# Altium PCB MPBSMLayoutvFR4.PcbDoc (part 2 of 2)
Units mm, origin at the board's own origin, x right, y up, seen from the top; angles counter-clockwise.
Board outline 131.7 x 110.39 mm, 4 copper layers (Top Layer, Power, GroundPlane, Bottom Layer), stack 2.286 mm thick; 157 components, 77 nets, 430 pads, 122 vias.
Unrouted connection lines stored in the file: 1.

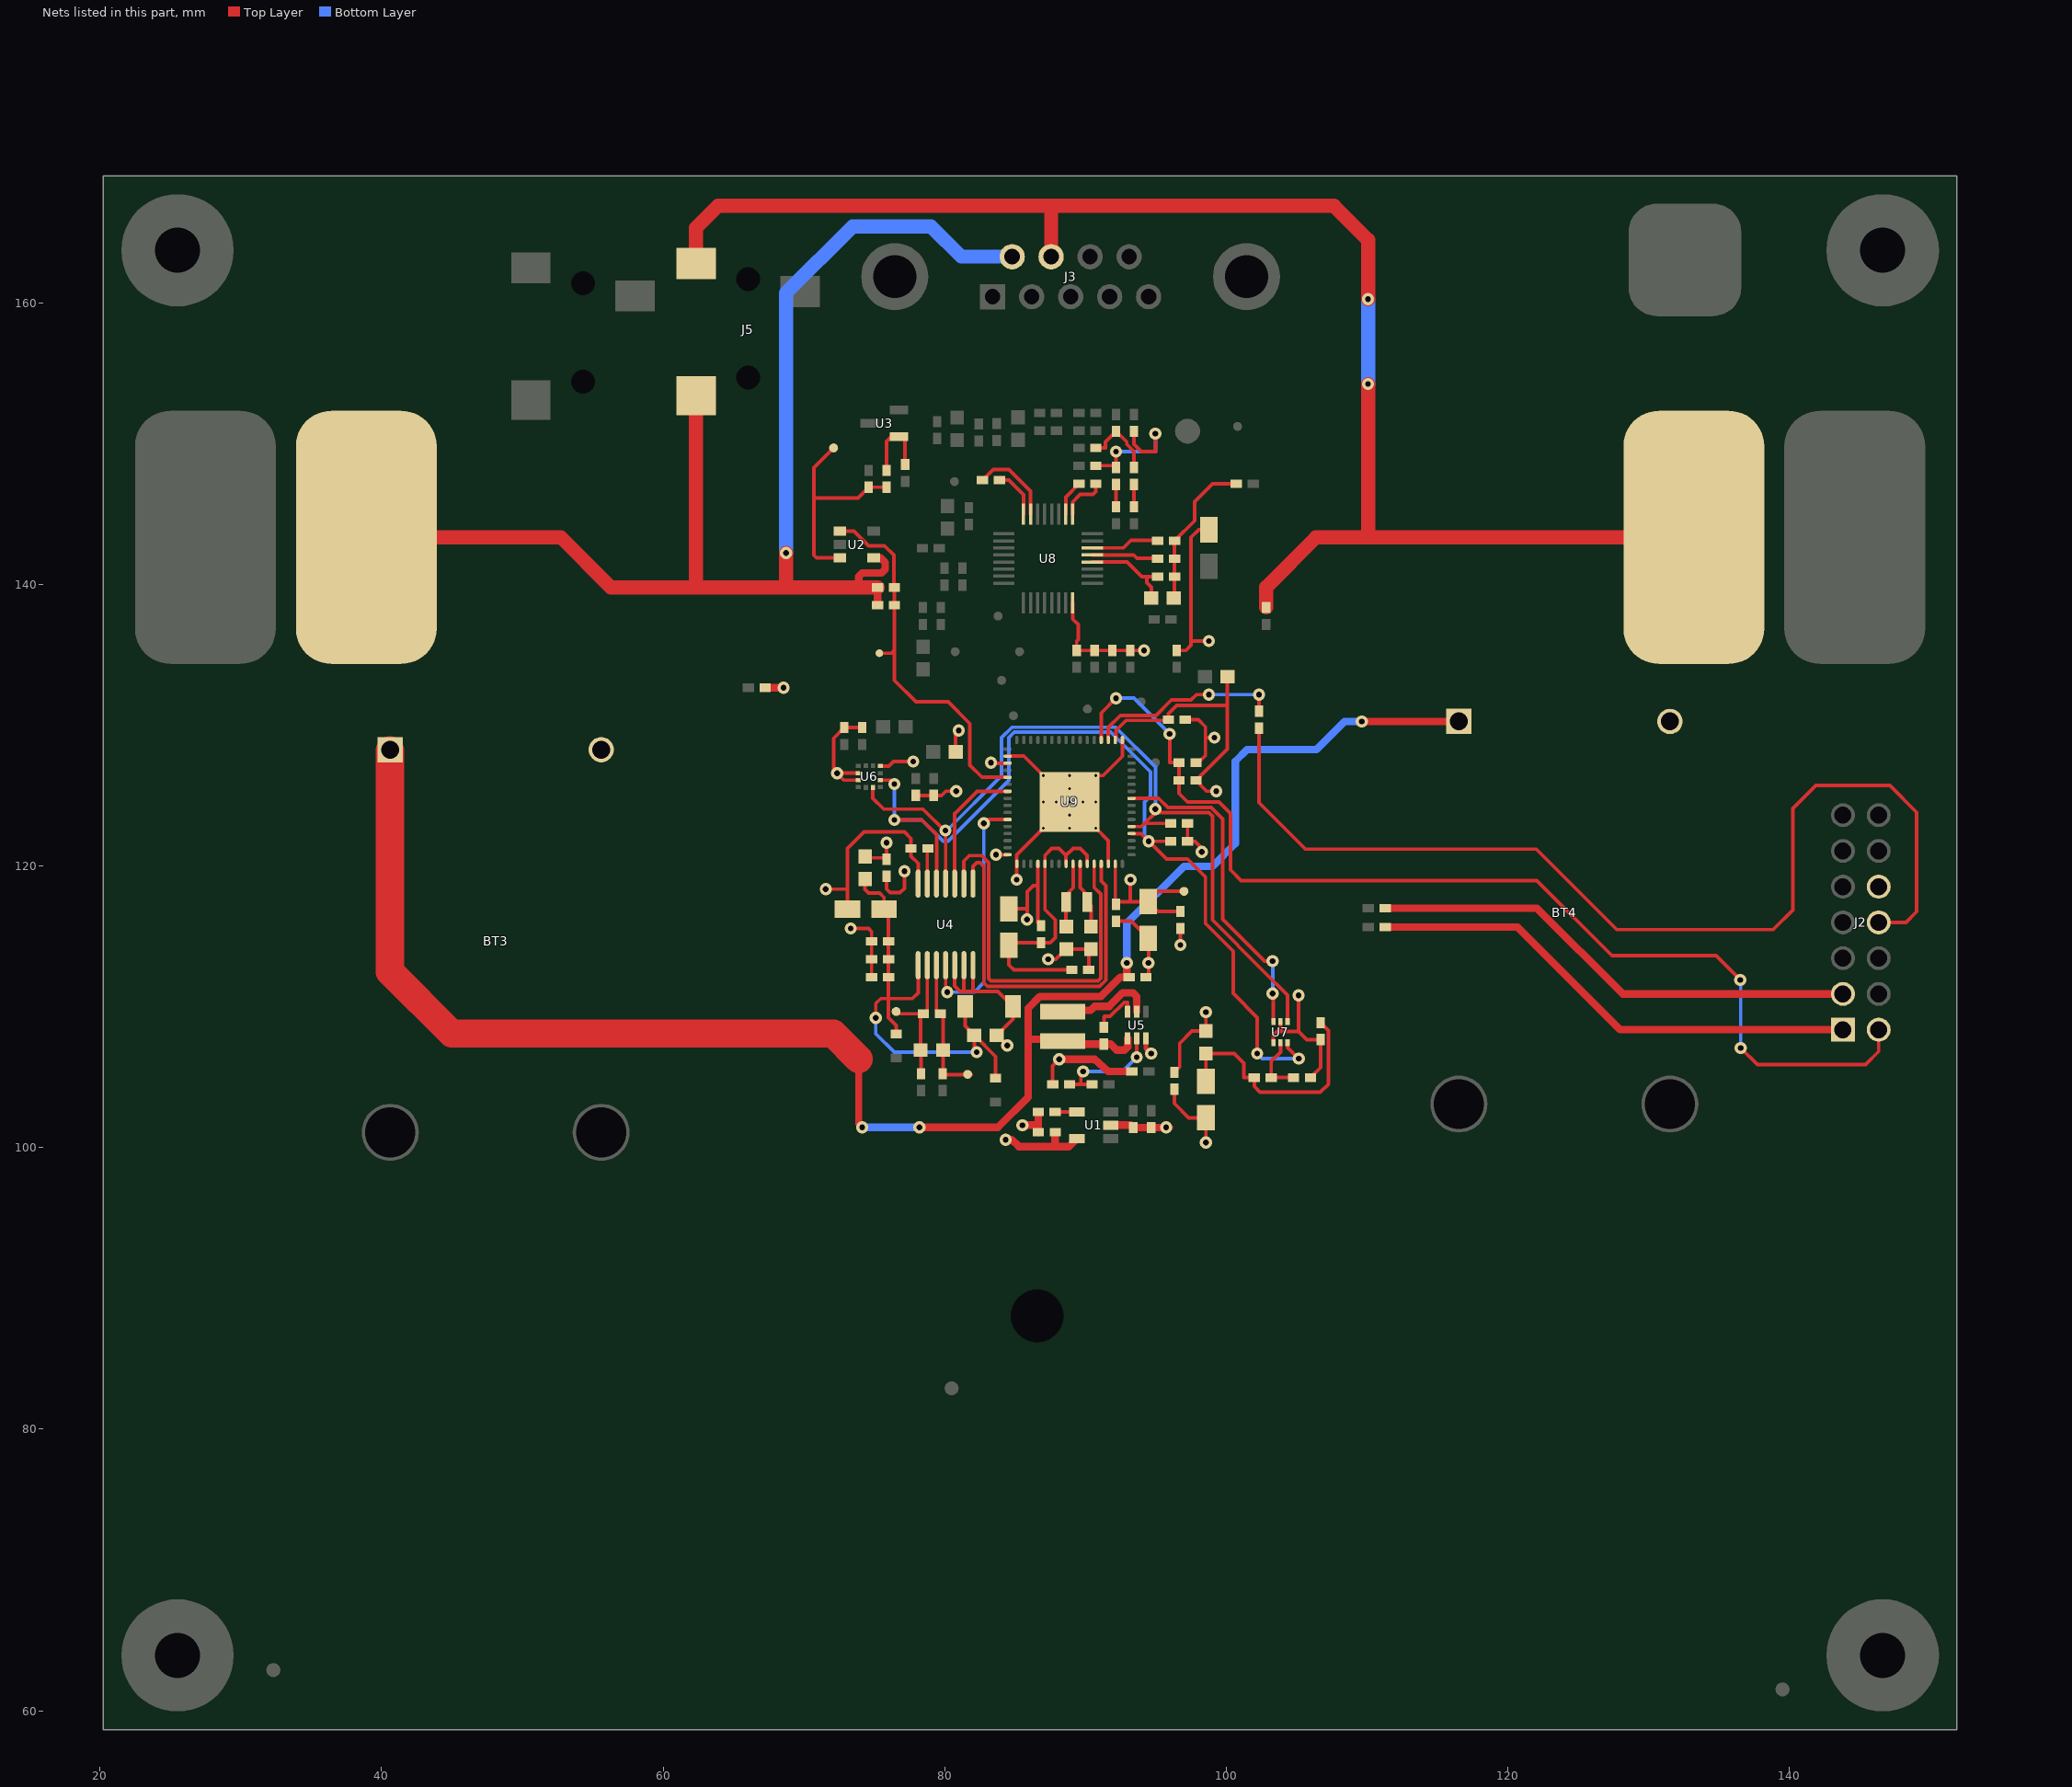
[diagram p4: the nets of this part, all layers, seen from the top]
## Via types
v1: diameter 0.864, hole 0.406, Top Layer to Bottom Layer, 109 vias
v2: diameter 0.5, hole 0.2, Top Layer to Bottom Layer, 13 vias

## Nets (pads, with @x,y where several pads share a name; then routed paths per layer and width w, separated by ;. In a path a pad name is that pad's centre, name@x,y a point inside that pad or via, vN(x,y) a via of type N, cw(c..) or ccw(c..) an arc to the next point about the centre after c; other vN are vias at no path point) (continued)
BOOST_INPUT: BT3.1 BT4.1 C34.1 L7.1 R16.1 U5.1 | length 128.2
  Top Layer w0.254: L7.1@88.393,107.681 L7.1@88.402,107.672 ; v1(92.939,113.132) v1@93.101,112.97
  Top Layer w0.5: 73.889,106.299 73.889,101.702 v1(74.143,101.448)
  Top Layer w0.54: v1(78.207,101.448) 83.795,101.448 85.928,103.581 85.928,109.906 86.766,110.744 91.11,110.744 92.481,112.116 C34.1@93.101,112.116 ; 85.928,107.696 L7.1@88.393,107.681 ; L7.1@88.612,107.35 R16.1@91.313,107.35 91.799,107.35 92.215,106.934 92.786,106.934 93,107.148 U5.1@93,107.762 ; C34.1@92.939,112.278 v1(92.939,113.132) ; v1(109.627,130.278) BT4.1@116.533,130.278
  Top Layer w2: BT3.1@40.589,128.22 40.589,112.497 44.983,108.102 72.085,108.102 73.889,106.299
  Bottom Layer w0.54: v1(74.143,101.448) v1(78.207,101.448) ; v1(92.939,113.132) 92.939,115.926 97.003,119.99 99.035,119.99 100.651,121.606 100.651,127.448 101.49,128.287 106.418,128.287 107.189,129.058 108.408,130.278 v1(109.627,130.278)
DVCC: 1.1 C1.1 C5.1 C6.1 C10.1 C14.1 C18.1 L1.1 L2.1 L3.1 L5.1 R1.1 R6.2 R31.1 R32.1 U1.5 U9.18 U9.35 U9.48 U9.63 | length 53
  Top Layer w0.254: L1.1@74.143,120.59 75.721,120.59 C10.1@75.744,120.613 ; C10.1@75.87,120.488 v1(75.87,121.666) ; L3.1@80.785,128.118 80.785,129.426 v1(81.001,129.642) ; v1@83.331,127.312 U9.35@84.475,127.312 ; v1(83.657,120.812) U9.48@84.475,120.812 ; U9.63@92.125,120.162 92.125,117.339 C6.1@92.177,117.288 ; U9.18@92.125,128.962 92.172,129.008 92.172,129.637 92.891,130.356 95.847,130.356 C18.1@95.895,130.404 95.895,130.82 96.495,131.42 100.051,131.42 ; C6.1@92.369,117.48 C1.1@94.463,117.48 ; 93.196,117.483 v1(93.196,119.027) ; C14.1@96.319,105.35 96.698,105.728 96.698,107.414 97.569,108.286 L2.1@98.56,108.286 v1(98.56,109.621) ; R1.1@96.749,116.78 95.163,116.78 C1.1@94.463,117.48 ; 1.1@97.003,118.212 95.195,118.212 C1.1@94.463,117.48 ; R32.1@97.257,123.038 R31.1@97.257,121.768 97.765,121.768 98.273,121.26 v1(98.273,121.006) ; v1(99.289,125.324) 98.619,125.324 R6.2@97.857,126.086 100.089,128.318 L5.1@100.089,133.452
  Top Layer w0.54: v1(84.328,100.559) v1@84.734,100.559 ; 84.76,100.584 85.268,100.076 87.854,100.076 ; C5.1@87.854,101.092 87.854,100.076 ; U1.5@89.402,100.65 88.828,100.076 87.854,100.076
  other v1: 83.287,127.356
EL_GSR1: C26.2 J3.6 J5.2 R10.1 TP2.1 U2.4 | length 96.7
  Top Layer w0.254: U2.4@74.951,141.9 75.463,141.9
  Top Layer w0.54: 73.889,139.852 73.889,140.564 74.143,140.818 75.529,140.818 75.783,141.072 75.783,141.58 75.463,141.9 ; C26.2@75.229,138.532 R10.1@75.229,139.802
  Top Layer w1: TP2.1@38.913,143.358 52.73,143.358 56.286,139.802 68.707,139.802 ; 62.34,139.835 J5.2@62.34,153.415 ; v1(68.732,142.24) 68.732,139.827 68.707,139.802 ; R10.1@75.229,139.802 68.707,139.802
  Bottom Layer w1: v1(68.732,142.24) 68.732,160.706 73.457,165.43 79.045,165.43 81.181,163.294 J3.6@84.796,163.294
EL_GSR2: J3.7 J5.1 R9.2 TP1.1 | length 110
  Top Layer w1: J5.1@62.34,162.815 62.34,165.362 63.881,166.903 107.671,166.903 110.084,164.49 v1(110.084,160.274) ; J3.7@87.566,163.294 87.566,166.89 ; R9.2@102.845,138.37 102.845,139.827 106.375,143.358 110.084,143.358 ; v1(110.084,154.254) 110.084,143.358 ; TP1.1@133.223,143.358 110.084,143.358
  Bottom Layer w1: v1(110.084,154.254) v1(110.084,160.274)
GND: BT3.2 BT4.2 C1.2 C3.2 C4.2 C5.2 C6.2 C8.2 C9.2 C10.2 C11.2 C12.2 C13.2 C14.2 C15.2 C16.2 C17.2 C18.2 C19.2 C20.2 C21.2 C25.2 C27.2 C28.2 C29.1 C32.2 C33.2 C34.2 C35.2 C36.2 C37.2 C38.2 C41.2 C42.2 C58.2 C59.2 J2.10 R2.1 R3.1 R17.1 U1.2 U4.5 U4.6 U4.7 U4.14 U5.3 U6.4 U6.8 U6.9 U7.2 U7.4 U8.24 U9.17 U9.34 U9.49 U9.62 U9.65 | length 144.3
  Top Layer w0.254: v1(71.552,118.364) 73.097,118.364 ; C9.2@73.097,116.942 73.097,118.364 ; v1(73.33,115.57) 74.6,115.57 74.813,115.357 C27.2@74.813,114.656 C11.2@74.813,113.386 C28.2@74.813,112.116 ; U6.9@73.876,126.111 72.847,126.111 v1(72.365,126.594) ; U6.8@73.876,126.611 72.382,126.611 v1(72.365,126.594) ; C37.2@74.143,129.847 C16.2@72.873,129.847 72.111,129.085 72.111,126.848 v1(72.365,126.594) ; U6.4@75.426,127.111 76.029,127.111 76.351,127.433 v1(77.771,127.433) ; C10.2@75.87,119.288 75.87,118.364 76.124,118.11 76.828,118.11 77.14,118.422 v1(77.14,119.634) ; C36.2@77.953,125.024 C17.2@79.223,125.024 79.778,125.024 80.078,125.324 v1(80.823,125.324) ; U4.14@78.117,118.764 78.117,120.193 77.607,120.704 C29.1@77.607,121.26 77.607,121.961 77.14,122.428 74.265,122.428 73.097,121.26 73.097,118.364 ; U4.5@80.717,112.964 80.717,111.484 81.102,111.1 82.017,111.1 ; 81.367,111.137 U4.6@81.367,112.964 ; U4.7@82.017,112.964 82.017,111.1 ; v1(84.451,107.266) 84.426,107.266 C33.2@83.701,107.991 84.855,109.145 C32.2@84.855,110.023 83.778,111.1 82.017,111.1 ; U9.34@84.475,127.812 85.625,127.812 v2(87,126.437) v2(88.875,124.562) ; v1(85.124,119.033) U9.49@85.124,120.162 85.124,120.811 v2(87,122.687) v2(88.875,124.562) ; v1(85.522,101.6) v1@85.534,101.613 ; v1(87.351,113.386) 87.897,113.386 88.621,114.11 C58.2@90.399,114.11 ; R17.1@87.675,104.496 87.675,105.812 v1(88.137,106.274) ; U8.24@89.101,138.704 89.101,137.544 89.483,137.162 89.483,136.099 89.383,135.999 C42.2@89.383,135.322 C41.2@90.653,135.322 C19.2@91.923,135.322 C20.2@93.193,135.322 v1@94.097,135.322 ; R2.1@90.237,112.624 C58.2@90.237,113.948 ; U9.62@91.625,120.162 91.625,121.811 v2(90.75,122.687) v2(88.875,124.562) ; C6.2@92.177,115.888 C6.2@92.177,116.088 93.255,116.088 C1.2@94.463,114.88 94.481,114.861 v1(94.481,113.132) 94.481,112.296 C34.2@94.301,112.116 C34.2@94.463,111.954 ; U9.17@92.626,128.962 92.626,127.805 91.258,126.437 v2(90.75,126.437) v2(88.875,124.562) ; C3.2@93.228,101.6 C3.2@93.401,101.428 ; v1(95.733,101.448) 95.733,101.194 v1@95.967,101.428 ; C14.2@96.319,104.15 96.319,103.147 97.345,102.122 C12.2@98.56,102.122 v1(98.56,100.374) ; C21.2@96.495,135.322 97.145,135.322 97.511,135.687 97.511,143.358 98.049,143.896 C15.2@98.781,143.896 C15.2@98.781,144.374 ; C18.2@97.095,130.404 98.019,130.404 98.527,129.896 98.527,129.134 ; 97.511,135.992 v1(98.781,135.992) ; C25.2@97.857,127.356 98.019,127.356 98.527,127.864 98.527,129.134 ; v1(99.162,129.134) 98.527,129.134 ; U7.4@103.359,107.456 103.359,108.011 103.609,108.261 105.15,108.261 ; 103.859,108.286 U7.2@103.859,108.956 ; v1(105.15,110.814) 105.15,108.261 ; C38.2@105.989,104.978 106.705,105.694 C13.2@106.705,107.68 105.731,107.68 105.15,108.261
  Top Layer w0.354: U5.3@94.3,107.762 94.3,107.046 v1(94.666,106.68)
  Top Layer w0.54: R3.1@67.257,132.67 v1(68.559,132.67) ; v1@85.534,101.613 86.654,101.613 ; C5.2@86.654,101.092 86.654,101.613 ; C8.2@86.654,102.54 86.654,101.613 ; v1(88.137,106.274) 89.453,106.274 90.653,106.274 91.618,105.41 C35.2@93.354,105.41 ; U1.2@91.802,101.6 C3.2@93.228,101.6 ; C3.2@93.401,101.428 C4.2@94.671,101.428 v1@95.967,101.428
  other v1: 94.158,135.322
  other v2: 88.875,122.687 88.875,123.624 87,124.562 87.937,124.562 89.812,124.562 90.75,124.562 88.875,125.499 88.875,126.437
GSR_ANALOG_OUTPUT: 2.1 C26.1 R10.2 U2.1 U9.37 | length 27.1
  Top Layer w0.254: U2.1@72.551,143.8 73.557,143.8 74.609,142.748 75.726,142.748 76.387,142.088 76.387,140.14 76.429,140.098 R10.2@76.429,139.802 C26.1@76.429,138.532 76.429,135.23 ; 2.1@75.362,135.128 76.327,135.128 ; 76.327,135.23 76.429,135.23 ; U9.37@84.475,126.312 82.654,126.312 81.788,127.178 81.788,130.124 80.239,131.674 77.953,131.674 76.429,133.198 76.429,135.23
JTAG_TCK: J2.8 R7.1 | length 75.1
  Top Layer w0.254: R7.1@102.337,129.804 102.337,124.511 105.639,121.209 122.022,121.209 127.737,115.494 138.862,115.494 140.259,116.891 140.259,124.104 141.884,125.73 147.142,125.73 149.047,123.825 149.047,116.764 148.285,116.002 J2.8@146.355,116.002
JTAG_TDO/TDI: C25.1 J2.2 R6.1 U9.20 | length 78
  Top Layer w0.254: U9.20@91.125,128.962 91.125,130.876 v1(92.177,131.928) ; v1(95.987,129.388) 95.987,127.356 C25.1@96.657,127.356 R6.1@96.657,126.086 96.657,125.162 97.257,124.562 99.483,124.562 100.305,123.74 100.305,119.736 101.067,118.974 122.072,118.974 127.406,113.64 134.798,113.64 v1(136.525,111.912) ; v1(136.55,107.086) 137.744,105.893 145.415,105.893 146.355,106.832 J2.2@146.355,108.382
  Bottom Layer w0.254: v1(92.177,131.928) 93.447,131.928 v1(95.987,129.388) ; v1(136.525,111.912) 136.55,111.938 v1(136.55,107.086)
JTAG_TEST/SBWTCK: R7.2 U9.19 | length 13.7
  Top Layer w0.254: U9.19@91.625,128.962 91.625,129.852 92.483,130.71 95.023,130.71 96.114,131.801 97.509,131.801 97.89,132.182 v1(98.781,132.182) ; R7.2@102.337,131.004 v1(102.337,132.182)
  Bottom Layer w0.254: v1(98.781,132.182) v1(102.337,132.182)
JTAG_VCC_TARGET_IN: J2.3 R5.1 | length 35
  Top Layer w0.54: R5.1@111.293,117.018 122.072,117.018 128.168,110.922 J2.3@143.815,110.922
JTAG_VCC_TOOL_OUT: J2.1 R4.1 | length 35.5
  Top Layer w0.54: R4.1@111.293,115.672 120.701,115.672 127.991,108.382 J2.1@143.815,108.382
MSP_AVCC: C2.1 C7.1 R1.2 U9.52 | length 9.3
  Top Layer w0.254: C2.1@84.876,116.972 85.857,116.972 ; v1(85.857,116.21) 85.857,116.972 ; C7.1@86.624,115.982 86.624,118.618 ; U9.52@86.624,120.162 86.624,118.618 ; v1(96.749,114.402) R1.2@96.749,115.58 ; 85.857,116.972 85.857,118.191 86.284,118.618 86.624,118.618
MSP_AVSS: C2.2 C7.2 R2.2 U9.53 U9.56 U9.59 | length 20.5
  Top Layer w0.254: C2.2@84.557,114.372 84.557,112.979 84.912,112.624 R2.2@89.037,112.624 ; C2.2@84.749,114.564 C7.2@86.843,114.564 87.513,114.564 87.859,114.91 87.859,116.18 87.124,116.914 U9.53@87.124,120.162 87.124,120.779 87.605,121.26 88.113,121.26 88.617,120.756 ; U9.56@88.625,120.162 88.625,120.756 89.129,121.26 89.637,121.26 90.125,120.771 U9.59@90.125,120.162
MSP_LFXIN: C59.1 U9.57 Y1.1 | length 4.1
  Top Layer w0.254: C59.1@88.621,115.71 88.621,117.438 Y1.1@88.633,117.45 ; Y1.1@88.633,117.97 89.125,118.462 U9.57@89.125,120.162
MSP_LFXOUT: C58.1 U9.58 Y1.2 | length 4.3
  Top Layer w0.254: U9.58@89.625,120.162 89.625,118.477 Y1.2@90.133,117.97 ; Y1.2@90.133,117.45 90.399,117.184 C58.1@90.399,115.71
MSP_P1.0_INT: U4.10 U9.39 | length 9.4
  Top Layer w0.254: U4.10@80.717,118.764 80.717,123.749 ; 80.733,123.749 82.296,125.312 U9.39@84.475,125.312
MSP_P2.7_INT: U7.3 U9.9 | length 23.4
  Top Layer w0.254: U9.9@93.275,124.812 95.198,124.812 95.856,124.154 98.935,124.154 99.743,123.346 99.743,116.234 102.718,113.259 v1(103.302,113.259) ; v1(103.302,110.947) 103.353,110.998 103.359,110.992 U7.3@103.359,108.956
  Bottom Layer w0.254: v1(103.302,110.947) v1(103.302,113.259)
MSP_P4.0_INT: U4.9 U9.60 | length 28.4
  Top Layer w0.254: U4.9@81.367,118.764 81.367,120.356 81.763,120.752 82.629,120.752 83.133,120.248 83.133,112.016 83.287,111.862 90.907,111.862 91.091,112.046 91.091,113.506 91.101,113.516 91.101,114.704 91.091,114.713 91.091,115.106 91.101,115.116 91.101,116.304 91.091,116.313 91.091,118.027 90.625,118.493 U9.60@90.625,120.162
MSP_P4.1_INT: U4.8 U9.61 | length 27.8
  Top Layer w0.254: U4.8@82.017,118.764 82.017,119.99 82.271,120.244 82.525,120.244 82.779,119.99 82.779,111.718 83.043,111.454 91.007,111.454 ; 91.007,111.461 91.445,111.9 91.445,113.36 91.455,113.369 91.455,118.612 91.125,118.942 U9.61@91.125,120.162
MSP_P9.3_OUT: U4.4 U9.43 | length 18
  Top Layer w0.254: U4.4@80.067,112.964 80.067,111.169 v1(80.188,111.049) ; v1(82.779,123.038) 83.053,123.312 U9.43@84.475,123.312
  Bottom Layer w0.254: v1(80.188,111.049) 82.11,111.049 82.779,111.718 v1(82.779,123.038)
MSP_UCB0SCL_TMP103_SCL_RF430CL330HCPW_SCL: R32.2 U4.11 U6.12 U7.1 U9.5 | length 59.3
  Top Layer w0.254: U6.12@74.901,125.586 74.901,124.82 75.667,124.054 78.461,124.054 v1@80.017,122.497 ; U4.11@80.067,118.764 v1@80.067,122.447 ; U9.5@93.275,122.812 93.983,122.812 94.209,123.038 ; v1(94.971,124.054) v1@94.971,123.8 ; R32.2@95.895,123.038 94.209,123.038 ; U7.1@104.359,108.956 104.359,110.83 102.642,112.547 99.035,116.18 99.035,123.546 98.781,123.8 v1@94.971,123.8 ; 94.209,123.038 v1@94.971,123.8
  Bottom Layer w0.254: v1(80.059,122.539) 80.067,122.531 80.067,122.447 84.049,126.428 84.049,129.134 84.781,129.866 92.146,129.866 94.971,127.042 v1(94.971,124.054)
MSP_UCB0SDA_TMP103_SDA_RF430CL330HCPW_SDA: R31.2 U4.12 U6.2 U7.6 U9.4 | length 67.5
  Top Layer w0.254: U6.2@75.426,126.111 76.149,126.111 v1(76.429,125.832) ; v1(76.429,123.292) 78.375,123.292 79.434,122.233 79.434,118.78 U4.12@79.417,118.764 ; U9.4@93.275,122.312 93.955,122.312 v1(94.499,121.768) ; R31.2@96.057,121.768 v1(94.499,121.768) ; v1(102.208,106.682) 102.208,109.247 100.495,110.96 100.495,113.957 98.527,115.926 98.527,119.228 97.257,120.498 95.769,120.498 v1(94.499,121.768) ; U7.6@104.359,107.456 104.359,107.122 v1(105.154,106.326)
  Bottom Layer w0.254: v1(76.429,125.832) v1(76.429,123.292) 78.375,123.292 79.899,121.768 80.239,121.768 84.557,126.086 84.557,129.134 84.935,129.512 91.798,129.512 94.617,126.694 94.617,124.97 94.209,124.562 94.209,122.058 v1(94.499,121.768) ; v1(102.208,106.682) 102.563,106.326 v1(105.154,106.326)
Net3_1: 3.1 R11.1 R12.2 U2.3 | length 15.6
  Top Layer w0.254: 70.703,146.152 73.84,146.152 R12.2@74.605,146.917 R11.1@75.875,146.917 ; 3.1@72.111,149.708 70.703,148.3 70.703,142.088 70.891,141.9 U2.3@72.551,141.9
Net4_1: 4.1 C30.1 C31.1 R13.1 U4.2 | length 9.9
  Top Layer w0.254: 4.1@76.551,109.676 76.712,109.515 C31.1@78.491,109.515 ; R13.1@78.329,105.255 78.329,106.903 C30.1@78.291,106.941 78.291,109.315 C31.1@78.491,109.515 ; U4.2@78.767,112.964 78.767,109.791 C31.1@78.491,109.515
Net5_1: 5.1 C30.2 C31.2 R14.1 U4.3 | length 9.9
  Top Layer w0.254: U4.3@79.417,112.964 79.417,109.788 C31.2@79.691,109.515 79.891,109.315 C30.2@79.891,106.941 79.891,105.293 79.988,105.197 5.1@81.885,105.197
NetC8_1: C8.1 U1.4 | length 1.6
  Top Layer w0.254: C8.1@87.849,102.54 87.859,102.55 U1.4@89.402,102.55
NetC29_2: C29.2 U4.13 | length 2.5
  Top Layer w0.254: U4.13@78.767,118.764 78.767,121.22 C29.2@78.807,121.26
NetC38_1: C38.1 R18.1 U7.5 | length 4.3
  Top Layer w0.254: U7.5@103.859,107.456 103.859,106.784 103.195,106.12 R18.1@103.195,104.978 C38.1@104.789,104.978
NetC43_1: C43.1 R19.2 R20.2 R21.2 R22.1 | length 10.9
  Top Layer w0.254: C43.1@96.333,139.094 R20.2@96.333,140.564 R21.2@96.333,141.834 96.333,141.876 R19.2@96.333,143.104 97.765,144.536 97.765,145.898 98.485,146.618 99.035,147.168 R22.1@100.721,147.168
NetC43_2: C43.2 R20.1 U8.28 | length 6.7
  Top Layer w0.254: U8.28@90.5,141.603 92.953,141.603 93.993,140.564 94.361,140.564 ; C43.2@94.679,139.04 94.679,139.818 94.361,140.135 94.361,140.564 ; R20.1@95.133,140.564 94.361,140.564
NetC45_1: C45.1 U8.2 | length 2.6
  Top Layer w0.254: U8.2@88.601,145.003 88.601,146.224 C45.1@89.545,147.168
NetC45_2: C45.2 U8.1 | length 3.4
  Top Layer w0.254: U8.1@89.101,145.003 89.101,145.87 89.637,146.406 90.538,146.406 90.745,146.612 C45.2@90.745,147.168
NetC46_2: C46.2 C48.2 C49.2 | length 10.4
  Top Layer w0.254: C46.2@90.745,148.45 C49.2@92.048,148.45 ; C49.2@92.177,148.322 v1(92.177,149.454) ; C48.2@93.447,150.886 93.452,150.88 93.452,149.967 93.966,149.454 94.971,149.454 v1(94.971,150.724)
  Bottom Layer w0.254: v1(92.177,149.454) 94.971,149.454 v1(94.971,150.724)
NetC47_1: C47.1 U8.8 | length 3.5
  Top Layer w0.254: C47.1@83.887,147.422 84.557,147.422 85.601,146.378 U8.8@85.601,145.003
NetC47_2: C47.2 U8.7 | length 6
  Top Layer w0.254: C47.2@82.687,147.422 83.449,148.184 84.557,148.184 86.101,146.64 U8.7@86.101,145.003
NetC49_1: C49.1 R26.1 | length 1.6
  Top Layer w0.254: R26.1@92.177,145.528 C49.1@92.177,147.122
NetC52_2: C52.2 C53.2 C54.2 | length 5.3
  Top Layer w0.254: C54.2@90.745,149.708 91.415,149.708 91.415,150.124 C52.2@92.177,150.886 92.939,150.124 92.939,149.962 93.447,149.454 C53.2@93.447,148.322
NetC53_1: C53.1 R27.1 | length 1.6
  Top Layer w0.254: R27.1@93.447,145.528 C53.1@93.447,147.122
NetL7_2: L7.2 U5.5 | length 5.5
  Top Layer w0.254: 91.719,110.033 91.719,110.084
  Top Layer w0.54: L7.2@89.84,109.752 90.372,109.752 90.653,110.033 91.719,110.033 ; 91.719,110.084 92.3,110.664 92.634,110.998 93.396,110.998 93.65,110.744 U5.5@93.65,109.662
NetR8_1: R8.1 R11.2 U3.1 | length 5.5
  Top Layer w0.254: R11.2@75.875,148.117 75.875,150.17 76.241,150.536 77.191,150.536 R8.1@77.191,148.53
NetR15_1: R15.1 R17.2 U5.2 | length 8.1
  Top Layer w0.254: R17.2@88.875,104.496 89.672,104.496 ; v1(89.84,105.41) 89.672,105.242 89.672,104.496 ; R15.1@90.469,104.496 89.672,104.496 ; v1(93.65,106.426) U5.2@93.65,107.762
  Bottom Layer w0.254: v1(89.84,105.41) 92.634,105.41 v1(93.65,106.426)
NetR16_2: R16.2 U5.6 | length 3.5
  Top Layer w0.254: R16.2@91.313,108.55 91.313,109.271 91.364,109.322 91.745,109.322 92.75,110.327 92.989,110.327 92.989,109.672 U5.6@93,109.662
NetR19_1: R19.1 U8.30 | length 4.9
  Top Layer w0.254: U8.30@90.5,142.603 92.692,142.603 93.235,143.146 R19.1@95.133,143.146
NetR21_1: R21.1 U8.29 | length 4.7
  Top Layer w0.254: U8.29@90.5,142.103 93.431,142.103 93.659,141.876 R21.1@95.133,141.876
RF430_DVCC: C9.1 C11.1 C27.1 C28.1 C32.1 C33.1 D1.1 D2.1 L1.2 U4.1 | length 34
  Top Layer w0.254: 74.346,118.512 74.346,118.338 74.592,118.092 75.38,118.092 75.697,117.775 C9.1@75.697,116.942 C9.1@75.921,117.166 ; v1(75.108,109.22) 75.108,110.236 75.463,110.592 76.007,110.592 ; C28.1@76.013,112.116 C11.1@76.013,113.386 C27.1@76.013,114.656 C9.1@76.013,116.626 ; C28.1@76.104,112.024 76.007,111.926 76.007,110.592 ; D1.1@76.551,108.079 76.551,108.691 76.007,109.235 76.007,110.592 ; U4.1@78.117,112.964 78.117,111.01 77.699,110.592 76.007,110.592 ; C32.1@81.455,110.023 81.455,108.637 C33.1@82.101,107.991 ; v1(82.271,106.782) 82.101,106.951 C33.1@82.101,107.991 ; D2.1@83.617,104.989 83.617,106.475 C33.1@82.101,107.991
  Bottom Layer w0.254: v1(75.108,109.22) 75.108,108.102 76.429,106.782 v1(82.271,106.782)
TMP_DVCC: C12.1 C13.1 L2.2 R18.2 | length 17.6
  Top Layer w0.254: C12.1@98.56,104.722 L2.2@98.56,106.686 100.576,106.686 101.268,105.994 101.268,104.978 R18.2@101.995,104.978 101.995,104.354 102.406,103.943 106.687,103.943 107.255,104.512 107.255,108.33 C13.1@106.705,108.88
pads on no net: BT3.3 BT3.4 BT4.3 BT4.4 FID1.1 FID2.1 FID3.1 H1.0 H2.0 H3.0 H4.0 H5.1 H6.1 H7.1 H8.1 H9.0 H10.0 H11.0 H12.0 J2.4 J2.5 J2.6 J2.7 J2.9 J2.11 J2.12 J2.13 J2.14 J3.3 J3.5 J3.8 J3.9 J4.4 J4.5 J5.3 J5.4 J5.5 U3.3 U6.10 U8.17 U9.1 U9.2 U9.3 U9.6 U9.7 U9.8 U9.10 U9.11 U9.12 U9.13 U9.15 U9.21 U9.22 U9.23 U9.24 U9.36 U9.40 U9.41 U9.42 U9.44 U9.45 U9.46 U9.47 U9.50 U9.51 U9.54 U9.55 U9.64

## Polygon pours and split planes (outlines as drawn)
ADS_DVCC on Power (split plane): 101.191,142.288 101.191,131.727 100.556,131.092 77.447,131.092 76.812,131.727 76.812,133.144 78.006,134.338 92.075,134.338 92.125,134.348 92.167,134.376 97.094,139.304 97.122,139.346 97.132,139.395 97.132,142.796 97.541,143.205 100.274,143.205
MSP_AVCC on Power (split plane): 86.367,117.065 86.713,116.61 86.713,112.624 86.723,112.574 86.751,112.532 86.793,112.504 86.843,112.494 94.809,112.494 94.858,112.504 94.9,112.532 95.824,113.456 95.852,113.498 95.862,113.548 95.862,115.796 97.625,115.796 97.625,115.57 97.625,113.937 97.165,113.477 95.888,112.2 95.425,111.737 85.584,111.737 84.94,112.41 84.94,116.653 85.355,117.089
ADS_AVCC on Power (split plane): 89.507,154.534 89.466,146.998 80.747,147.043 80.722,147.038 80.698,147.033 80.697,147.033 80.676,147.019 80.656,147.006 80.655,147.005 80.641,146.984 80.627,146.964 80.627,146.963 80.622,146.939 80.617,146.914 80.617,143.104 80.627,143.054 80.655,143.012 80.697,142.984 80.747,142.974 85.443,142.974 85.443,141.201 82.271,141.201 82.221,141.191 82.179,141.163 82.151,141.121 82.141,141.072 82.141,135.359 75.999,135.359 75.999,139.09 75.989,139.14 75.961,139.182 73.764,141.379 73.764,145.59 76.781,148.607 77.92,148.607 77.944,148.612 77.969,148.616 77.969,148.617 77.99,148.631 78.011,148.644 78.011,148.645 78.025,148.665 78.039,148.686 78.039,148.687 78.044,148.711 78.049,148.736 78.081,154.658 89.507,154.658
DVCC on Power (split plane): 151.407,158.471 151.407,59.159 20.729,59.159 20.729,168.527 151.407,168.527
ADS_AVSS on GroundPlane (split plane): 151.407,158.471 151.407,133.276 100.942,133.276 100.942,137.008 100.932,137.057 100.904,137.099 100.862,137.127 100.813,137.137 97.765,137.137 97.715,137.127 97.673,137.099 97.645,137.057 97.635,137.008 97.635,135.765 95.303,135.765 95.303,136.398 95.293,136.448 95.265,136.49 95.223,136.518 95.174,136.527 68.25,136.527 68.2,136.518 68.158,136.49 66.583,134.915 66.555,134.873 66.546,134.823 66.546,129.898 64.649,128.002 59.328,128.002 56.911,130.419 56.869,130.447 56.82,130.457 54.381,130.457 54.332,130.447 54.29,130.419 53.566,129.695 20.729,129.695 20.729,168.527 151.407,168.527
GND on GroundPlane (split plane): 100.683,133.147 100.693,133.097 100.721,133.055 100.763,133.027 100.813,133.017 151.407,133.017 151.407,59.159 20.729,59.159 20.729,129.436 53.619,129.436 53.669,129.446 53.711,129.474 54.435,130.198 56.766,130.198 59.183,127.781 59.225,127.753 59.274,127.743 64.703,127.743 64.753,127.753 64.795,127.781 66.767,129.753 66.795,129.795 66.804,129.845 66.804,134.77 68.303,136.269 95.044,136.269 95.044,135.636 95.054,135.586 95.082,135.544 95.124,135.516 95.174,135.507 97.765,135.507 97.814,135.516 97.856,135.544 97.884,135.586 97.894,135.636 97.894,136.878 100.683,136.878

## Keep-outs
Keep-Out Layer:
  text ".Layer_Name" at 157.226,108.306 h1.52

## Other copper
Top Layer:
  text ".Layer_Name" at 157.226,156.566 h1.52
Bottom Layer:
  text ".Layer_Name" at 157.226,154.026 h1.52
  text "SVN:" at 48.501,114.91 h1.52 r90
  text ".VersionControl_RevNumber" at 48.501,107.823 h1.52 r90
  text "UL94V-0" at 54.534,69.774 h1.52 r90
Power (plane layer: these items are gaps in the copper):
  rectangle: 73.635,69.952 99.035,99.67
  lines w0.254: 97.755,115.57 97.755,115.926 ; 97.755,115.926 97.351,115.926 95.733,115.926 95.733,113.548 94.809,112.624 87.062,112.624 86.843,112.624 86.843,116.654 86.433,117.193 85.301,117.219 84.811,116.705 84.811,112.358 85.529,111.608 90.997,111.608 95.479,111.608 95.979,112.108 97.257,113.386 97.755,113.884 97.755,115.926 ; 73.635,141.326 75.87,139.09 75.87,135.23 80.043,135.23 82.271,135.23 82.271,141.072 85.573,141.072 85.573,143.104 80.747,143.104 80.747,146.914 89.595,146.868 89.637,154.534 89.637,154.788 77.953,154.788 77.92,148.736 76.727,148.736 73.635,145.644 73.635,141.326 ; 76.683,131.674 76.683,133.198 77.953,134.468 92.075,134.468 97.003,139.395 97.003,142.85 97.487,143.334 100.328,143.334 101.321,142.342 101.321,131.674 100.609,130.962 77.394,130.962 76.683,131.674
GroundPlane (plane layer: these items are gaps in the copper):
  rectangle: 73.635,69.952 99.035,99.67
  lines w0.254: 20.218,127.889 20.218,129.565 53.619,129.565 54.381,130.327 56.82,130.327 59.274,127.873 64.703,127.873 66.675,129.845 66.675,134.823 68.25,136.398 95.174,136.398 95.174,135.636 97.765,135.636 97.765,137.008 100.813,137.008 100.813,133.147 151.917,133.147 151.917,128.676

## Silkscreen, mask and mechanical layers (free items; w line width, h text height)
Top Overlay:
  region: 95.174,77.724 95.174,85.344 92.634,85.344 92.634,77.724
  lines w1: 79.35,70.891 72.72,70.891 72.72,98.222 99.847,98.222 99.847,70.891 92.888,70.891
  lines w2: 47.777,60.96 47.777,132.918 47.777,167.716 ; 124.485,61.646 124.485,167.157
  text "GSR" at 129.642,153.289 h4
  text "ECG" at 141.021,153.238 h4
  text "ECG" at 23.546,152.806 h4
  text "GSR" at 36.195,152.756 h4
  text "GND" at 58.903,129.794 h1.02
  text ".Layer_Name" at 157.226,128.626 h1.52
  text "JTAG" at 105.588,126.009 h1.02
  text "VCC" at 43.866,125.501 h1.02
  text "BAT" at 109.398,122.987 h1.02
  text "VCC" at 60.833,121.361 h1.02
  text "GND" at 45.695,121.158 h1.02
  text "FOR DEMO PURPOSES ONLY" at 75.336,94.259 h1.02
  text "MPBSM" at 78.918,91.44 h1.02
  text "REV B" at 78.918,89.916 h1.02
  text "TI" at 91.008,87.884 h1.52
  text "©" at 93.65,87.63 h2.67
  text ".CopyrightYear" at 83.998,77.724 h1.52
  text "MADE IN U.S." at 77.648,75.438 h1.52
  text "NFC Antenna" at 80.924,70.155 h2
  text "-" at 49.758,67.666 h1.52 r90
  text "Place phone here" at 51.46,61.925 h10
Bottom Overlay:
  text ".Layer_Name" at 157.226,126.086 h1.52
Top Paste:
  text ".Layer_Name" at 157.226,123.546 h1.52
Bottom Paste:
  text ".Layer_Name" at 157.226,121.006 h1.52
Top Solder:
  text ".Layer_Name" at 157.226,118.466 h1.52
  text ".Layer_Name" at 157.226,115.926 h1.52
Bottom Solder:
  text ".Layer_Name" at 157.226,113.386 h1.52
Drill Guide:
  text ".Layer_Name" at 157.226,110.846 h1.52
M1 Board Outline:
  lines w0.254: 20.218,58.649 151.917,58.649 151.917,169.037 20.218,169.037 20.218,58.649
  text ".Layer_Name" at 157.226,151.486 h1.52
M2 Board Dimensions:
  rectangle: 17.577,32.982 20.752,36.157
  rectangle: 20.752,29.807 30.277,32.982
  lines w0.178: 17.577,32.982 42.977,32.982 ; 20.752,29.807 20.752,36.157 ; 23.927,29.807 23.927,36.157 ; 30.277,29.807 30.277,36.157 ; 36.627,29.807 36.627,36.157 ; 17.577,29.807 42.977,29.807 42.977,36.157 17.577,36.157 17.577,29.807
  text ".Layer_Name" at 18.034,37.338 h1.52
M3 3D STEP Top:
  text ".Layer_Name" at 157.226,148.946 h1.52
M4 3D STEP Bottom:
  text ".Layer_Name" at 157.226,146.406 h1.52
M5 Assembly Top:
  lines w0.254: 10.16,16.607 177.8,16.607 ; 10.16,21.772 177.851,21.772 ; 10.16,26.937 10.16,11.443 111.887,11.443 177.851,11.443 177.851,26.937 10.173,26.937 10.173,11.443 50.19,11.443 ; 72.771,11.443 72.771,26.937 ; 104.953,21.772 104.953,26.937 ; 126.289,21.772 126.289,26.937 ; 142.088,11.278 142.088,16.43
  text "COMPONENTS MARKED 'DNP' SHOULD NOT BE POPULATED." at 46.876,32.144 h1.52
  text "ASSEMBLY VARIANT:" at 46.863,29.21 h1.52
  text ".VariantName" at 73.177,29.21 h1.52
  text "PCB VIEWED FROM TOP SIDE" at 11.773,23.58 h1.52
  text "BOARD #:" at 74.676,23.58 h1.52
  text ".PRJ_Number" at 88.532,23.58 h1.52
  text "REV:" at 109.982,23.58 h1.52
  text ".PCB_Rev" at 117.386,23.58 h1.52
  text "SVN REV:" at 131.267,23.58 h1.52
  text ".VersionControl_RevNumber" at 144.12,23.58 h1.52
  text "IGNORE ->" at 11.773,18.428 h1.52
  text "PLOT NAME =" at 11.773,13.199 h1.52
  text ".plot_File_Name" at 32.233,13.199 h1.52
  text "GENERATED    :" at 74.727,13.199 h1.52
  text ".Print_Date" at 96.812,13.199 h1.52
  text ".Print_Time" at 115.329,13.199 h1.52
  text "TEXAS INSTRUMENTS" at 147.447,13.199 h1.52
M6 Assembly Bottom:
  lines w0.254: 10.147,21.759 177.838,21.759 ; 10.198,16.595 177.838,16.595 ; 45.91,11.265 45.91,16.417 ; 61.709,21.759 61.709,26.924 ; 83.045,21.759 83.045,26.924 ; 115.227,11.43 115.227,26.924 ; 137.808,11.43 177.825,11.43 177.825,26.924 10.147,26.924 10.147,11.43 76.111,11.43 177.838,11.43 177.838,26.924
  text "COMPONENTS MARKED 'DNP' SHOULD NOT BE POPULATED." at 172.568,32.156 h1.52
  text ".VariantName" at 146.05,29.21 h1.52
  text "ASSEMBLY VARIANT:" at 172.441,29.21 h1.52
  text ".VersionControl_RevNumber" at 43.878,23.567 h1.52
  text "SVN REV:" at 56.731,23.567 h1.52
  text ".PCB_Rev" at 70.612,23.567 h1.52
  text "REV:" at 78.016,23.567 h1.52
  text ".PRJ_Number" at 99.466,23.567 h1.52
  text "BOARD #:" at 113.322,23.567 h1.52
  text "PCB VIEWED FROM BOTTOM SIDE" at 176.225,23.567 h1.52
  text "IGNORE ->" at 82.292,18.428 h1.52
  text "TEXAS INSTRUMENTS" at 40.551,13.187 h1.52
  text ".Print_Time" at 72.669,13.187 h1.52
  text ".Print_Date" at 91.186,13.187 h1.52
  text "GENERATED    :" at 113.271,13.187 h1.52
  text ".plot_File_Name" at 155.766,13.187 h1.52
  text "PLOT NAME =" at 176.225,13.187 h1.52
M9 Title Sheet:
  drawing of 57 lines, arcs and shapes, not listed
  text "1" at 36.369,243.091 h1.78
  text "2" at 99.758,243.091 h1.78
  text "3" at 162.988,243.091 h1.78
  text "4" at 226.657,243.091 h1.78
  text "5" at 290.131,243.091 h1.78
  text "6" at 353.758,243.091 h1.78
  text "A" at 6.998,214.058 h1.78
  text "A" at 382.918,214.058 h1.78
  text "B" at 6.998,153.606 h1.78
  text "B" at 382.918,153.606 h1.78
  text ".Layer_Name" at 157.226,143.866 h1.52
  text "C" at 6.998,93.281 h1.78
  text "C" at 382.918,93.281 h1.78
  text "PROJECT TITLE:" at 305.702,46.012 h1.14
  text ".PRJ_Title" at 306.972,42.626 h1.78
  text "DESIGNED FOR:" at 305.702,38.367 h1.14
  text ".PRJ_Customer" at 306.972,34.811 h1.78
  text "D" at 6.998,33.084 h1.78
  text "D" at 382.918,33.084 h1.78
  text "FILE NAME:" at 305.702,30.747 h1.14
  text ".PCB_File_Name_No_Path" at 306.972,27.699 h1.78
  text "Texas Instruments (TI) and/or its licensors do not warrant the accuracy or completeness of this specification" at 179.476,23.588 h1.14
  text "ENGINEER:" at 305.702,23.381 h1.14
  text "LAYOUT BY:" at 343.929,23.381 h1.14
  text "or any information contained therein. TI and/or its licensors do not warrant that this design will meet" at 178.334,20.726 h1.14
  text ".PRJ_Engineer" at 306.972,19.444 h1.78
  text ".PCB_Layout" at 345.211,19.444 h1.78
  text "the specifications, will be suitable for your application or fit for any particular purpose, or will operate in" at 178.334,17.865 h1.14
  text "ALTIUM DESIGNER VERSION:" at 343.929,15.507 h1.14
  text "an implementation. TI and/or its licensors do not warrant that the design is production worthy. You should" at 178.334,15.003 h1.14
  text "completely validate and test your design implementation to confirm the system functionality for your application." at 179.476,12.141 h1.14
  text ".print_Scale" at 306.972,12.12 h1.78
  text ".Application_BuildNumber" at 345.211,12.12 h1.78
  text "1" at 36.369,6.871 h1.78
  text "2" at 99.758,6.871 h1.78
  text "3" at 162.988,6.871 h1.78
  text "4" at 226.657,6.871 h1.78
  text "5" at 290.131,6.871 h1.78
  text "6" at 353.758,6.871 h1.78
M10 Fab Notes:
  drawing of 185 lines, arcs and shapes, not listed
  text "DESIGN INFORMATION" at 332.055,190.348 h1.52
  text "MIN. TRACK WIDTH:" at 315.683,185.776 h1.52
  text "8" at 343.527,185.776 h1.52
  text "MIL" at 347.458,185.776 h1.52
  text "MIN. CLEARANCE:" at 315.683,182.423 h1.52
  text "0.2" at 342.003,182.423 h1.52
  text "mm" at 347.458,182.423 h1.52
  text "MIN. VIA PAD SIZE:" at 315.683,179.07 h1.52
  text "24" at 342.766,179.07 h1.52
  text "MIL" at 347.458,179.07 h1.52
  text "0.05mm (2MIL)" at 333.336,175.471 h1.52
  text "MINIMUM ANNULAR RING" at 307.32,175.362 h1.52
  text "EXTERNAL" at 351.319,175.362 h1.52
  text "PER" at 312.4,172.364 h1.52
  text "IPC-D-275 CLASS 2 LEVEL C" at 317.988,172.364 h1.52
  text "MIL, HOLES" at 355.789,169.512 h1.52
  text "+/-" at 345.821,169.494 h1.52
  text "+/-" at 367.513,169.494 h1.52
  text "REGISTRATION TOLERANCES:" at 307.32,169.367 h1.52
  text "METAL" at 337.795,169.367 h1.52
  text "5" at 352.43,169.367 h1.52
  text "3" at 373.588,169.367 h1.52
  text "MIL" at 376.541,169.367 h1.52
  text "MATERIAL:" at 305.421,164.047 h1.52
  text "FR-4 High Tg" at 330.477,160.482 h1.52
  text "FR-408" at 316.115,160.265 h1.52
  text "X" at 326.579,160.265 h1.52
  text "OTHER" at 353.91,160.265 h1.52
  text "62 MIL (1.6mm) +/-10%" at 324.245,156.132 h1.52
  text "THICKNESS:" at 307.32,156.023 h1.52
  text "X" at 320.99,156.023 h1.52
  text "OTHER" at 356.882,156.023 h1.52
  text "TOLERANCE:" at 307.32,152.01 h1.52
  text "X" at 328.639,152.01 h1.52
  text "ANSI IPC-6012 TYPE 3 CLASS 2" at 333.387,152.01 h1.52
  text "OTHER +/-" at 333.387,148.047 h1.52
  text "BOW & TWIST:" at 307.32,144.06 h1.52
  text "X" at 328.639,144.06 h1.52
  text "ANSI IPC-6012 TYPE 3 CLASS 2" at 333.387,144.06 h1.52
  text ".Layer_Name" at 157.226,141.326 h1.52
  text "OTHER +/-" at 333.387,140.034 h1.52
  text "DRILLING:" at 305.421,136.516 h1.52
  text "REFERENCE:" at 307.32,133.544 h1.52
  text "X" at 323.785,133.544 h1.52
  text "AS SHOWN" at 328.535,133.544 h1.52
  text "X" at 346.671,133.544 h1.52
  text "NC_DRILL FILES" at 350.151,133.544 h1.52
  text "PTH MIN COPPER THICKNESS:" at 307.32,129.531 h1.52
  text "X" at 341.616,129.531 h1.52
  text "1MIL" at 345.096,129.531 h1.52
  text "OTHER" at 357.72,129.531 h1.52
  text "BOARD FINISH:" at 305.421,125.492 h1.52
  text "SILKSCREEN:" at 309.364,122.495 h1.52
  text "X" at 333.463,122.495 h1.52
  text "TOP" at 336.663,122.495 h1.52
  text "X" at 346.417,122.495 h1.52
  text "BOTTOM" at 349.643,122.495 h1.52
  text "SILKSCREEN COLOR:" at 310.634,118.26 h1.52
  text "X" at 333.436,118.253 h1.52
  text "WHITE" at 336.663,118.253 h1.52
  text "OTHER" at 349.643,118.253 h1.52
  text "SOLDER RESIST COLOR:" at 309.364,113.935 h1.52
  text "GREEN" at 327.011,109.892 h1.52
  text "BLUE" at 342.023,109.892 h1.52
  text "OTHER" at 355.688,109.892 h1.52
  text "X" at 323.785,109.644 h1.52
  text "IMMERSION GOLD (ENIG)" at 332.371,105.103 h1.52
  text "ENEPIG" at 366.344,105.02 h1.52
  text "SURFACE FINISH:" at 305.421,104.994 h1.52
  text "X" at 327.622,104.994 h1.52
  text "IMM. TIN/SILVER OR EQUIV" at 313.792,101.007 h1.52
  text "OTHER" at 350.151,101.007 h1.52
  text "ARRAY/PANEL:" at 305.421,96.46 h1.52
  text "CUT AND TRIM PER MECH LAYER 1" at 332.371,96.351 h1.52
  text "N.C. ROUTE" at 332.371,92.498 h1.52
  text "X" at 349.617,92.498 h1.52
  text "V. SCORE" at 354.367,92.498 h1.52
  text "CERTIFICATION:" at 305.421,89.018 h1.52
  text "MATERIALS AND WORKMANSHIP FOR ALL PCBS" at 323.836,89.018 h1.52
  text "TO MEET OR EXCEED THE REQUIREMENTS OF:" at 323.836,86.529 h1.52
  text "X" at 314.349,83.061 h1.52
  text "ANSI IPC-A-600F CLASS ->" at 317.88,83.061 h1.52
  text "X" at 359.512,83.061 h1.52
  text "2" at 362.533,83.061 h1.52
  text "1" at 354.532,83.023 h1.52
  text "3" at 371.525,83.023 h1.52
  text "X" at 314.402,79.01 h1.52
  text "UL 94V-0" at 317.88,79.01 h1.52
  text "X" at 335.026,79.01 h1.52
  text "RoHS" at 338.505,79.01 h1.52
  text "OTHER" at 354.873,79.01 h1.52
  text "PER ORDER" at 364.958,79.01 h1.52
  text "ADDITIONAL REQUIREMENTS:" at 305.193,75.302 h1.52
  text "MICROSECTION:" at 307.092,72.381 h1.52
  text "YES" at 330.098,72.381 h1.52
  text "REQUIRED" at 352.208,68.542 h1.52
  text "NONE" at 340.486,68.469 h1.52
  text "X" at 348.982,68.469 h1.52
  text "PER ORDER" at 367.245,68.469 h1.52
  text "BARE BOARD ELEC. TEST:" at 307.092,68.342 h1.52
  text "MANUFACTURER'S UL:" at 307.092,64.354 h1.52
  text "METAL" at 349.422,64.373 h1.52
  text "X" at 358.953,64.364 h1.52
  text "SILK" at 362.419,64.373 h1.52
  text "RAIL" at 336.702,64.245 h1.52
M11 Gerber Information:
  lines w0.254: 10.16,16.607 177.8,16.607 ; 10.16,21.772 177.851,21.772 ; 10.16,26.937 10.16,11.443 111.887,11.443 177.851,11.443 177.851,26.937 10.173,26.937 10.173,11.443 50.19,11.443 ; 72.771,11.443 72.771,26.937 ; 104.953,21.772 104.953,26.937 ; 126.289,21.772 126.289,26.937 ; 142.088,11.278 142.088,16.43
  text "ALL ARTWORK VIEWED FROM TOP SIDE" at 11.773,23.58 h1.52
  text "BOARD #:" at 74.676,23.58 h1.52
  text ".PRJ_Number" at 88.532,23.58 h1.52
  text "REV:" at 109.982,23.58 h1.52
  text ".PCB_Rev" at 117.386,23.58 h1.52
  text "SVN REV:" at 131.267,23.58 h1.52
  text ".VersionControl_RevNumber" at 144.12,23.58 h1.52
  text "LAYER NAME =" at 11.773,18.428 h1.52
  text "PLOT NAME =" at 11.773,13.199 h1.52
  text ".plot_File_Name" at 32.233,13.199 h1.52
  text "GENERATED    :" at 74.727,13.199 h1.52
  text ".Print_Date" at 96.812,13.199 h1.52
  text ".Print_Time" at 115.329,13.199 h1.52
  text "TEXAS INSTRUMENTS" at 147.447,13.199 h1.52
M12 Stackup:
  lines w0.152: 305.105,221.59 369.875,221.59 ; 305.105,224.241 369.875,224.241 ; 303.581,209.271 ccw(c304.444,209.271) 304.444,208.407 370.535,208.407 ccw(c370.535,209.271) 371.399,209.271 371.399,227.203 ccw(c370.535,227.203) 370.535,228.067 304.444,228.067 ccw(c304.444,227.203) 303.581,227.203 303.581,209.271
  text "The Stackup Legend below this is static." at 311.34,232.118 h1.52
  text "If you change the stackup, update the Legend." at 311.594,229.832 h1.52
  text "Layer Stack Up Detail for: Ref_Design.PcbDoc" at 305.105,225.072 h1.45
  text "Layer" at 305.105,223.251 h0.61
  text "Gerber" at 327.858,223.251 h0.61
  text "Copper" at 342.172,223.251 h0.61
  text "Dielectric" at 357.481,223.251 h0.61
  text "Name" at 305.105,222.032 h0.61
  text "Document" at 327.858,222.032 h0.61
  text "Thickness" at 342.172,222.032 h0.61
  text "Material" at 357.481,222.032 h0.61
  text "Top Solder Mask" at 305.105,219.67 h0.86
  text "(.GTS)" at 327.858,219.67 h0.86
  text "Solder Resist" at 357.481,219.67 h0.86
  text ".Layer_Name" at 284.988,218.186 h1.52
  text "Top Layer" at 305.105,217.213 h0.86
  text "(.GTL)" at 327.858,217.213 h0.86
  text "1.4mil" at 342.172,217.213 h0.86
  text "FR-4" at 357.481,215.984 h0.86
  text "Bottom Layer" at 305.105,214.755 h0.86
  text "(.GBL)" at 327.858,214.755 h0.86
  text "1.4mil" at 342.172,214.755 h0.86
  text "Bottom Solder Mask" at 305.105,212.298 h0.86
  text "(.GBS)" at 327.858,212.298 h0.86
  text "Solder Resist" at 357.481,212.298 h0.86
M13 Component Bodies Top:
  text ".Layer_Name" at 157.226,138.786 h1.52
M14 Component Bodies Bottom:
  text ".Layer_Name" at 157.226,136.246 h1.52
M15 Courtyards Top:
  text ".Layer_Name" at 157.226,133.706 h1.52
M16 Courtyards Bottom:
  text ".Layer_Name" at 157.226,131.166 h1.52
Drill Drawing:
  text ".Layer_Name" at 157.226,105.766 h1.52

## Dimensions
25.502,63.932 to 20.218,58.649 on M2 Board Dimensions
25.502,63.932 to 20.218,58.649 on M2 Board Dimensions
146.635,63.938 to 151.917,58.649 on M2 Board Dimensions
146.635,63.938 to 151.917,58.649 on M2 Board Dimensions
146.634,163.754 to 151.917,169.037 on M2 Board Dimensions
146.634,163.754 to 151.917,169.037 on M2 Board Dimensions
25.502,163.754 to 20.218,169.037 on M2 Board Dimensions
25.502,163.754 to 20.218,169.037 on M2 Board Dimensions
131.523,103.098 to 151.917,58.649 on M6 Assembly Bottom
131.523,103.098 to 151.917,58.649 on M6 Assembly Bottom
40.613,101.091 to 20.218,58.649 on M6 Assembly Bottom
40.613,101.091 to 20.218,58.649 on M6 Assembly Bottom
20.218,169.037 to 20.218,58.649 on M2 Board Dimensions
20.218,169.037 to 151.917,169.037 on M2 Board Dimensions
20.218,169.037 to 20.218,58.649 on M2 Board Dimensions
20.218,169.037 to 151.917,169.037 on M2 Board Dimensions
144.653,143.358 to 151.917,158.471 on M2 Board Dimensions
27.483,143.358 to 20.218,169.037 on M2 Board Dimensions
124.485,61.646 to 151.917,58.649 on M2 Board Dimensions
20.218,58.649 to 47.777,60.96 on M2 Board Dimensions
133.223,143.358 to 144.653,143.358 on M2 Board Dimensions
27.483,143.358 to 38.913,143.358 on M2 Board Dimensions
17.577,29.807 to 42.977,29.807 on M2 Board Dimensions
74.651,72.492 to 98.019,72.492 on M2 Board Dimensions
98.019,97.13 to 98.019,72.492 on M2 Board Dimensions
98.527,71.984 to 124.485,61.646 on M2 Board Dimensions
47.777,60.96 to 74.092,71.984 on M2 Board Dimensions
47.777,60.96 to 124.485,61.646 on M2 Board Dimensions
